VERSION 5.8 ;
BUSBITCHARS "[]" ;
DIVIDERCHAR "/" ;
UNITS
    DATABASE MICRONS 1000 ;
END UNITS

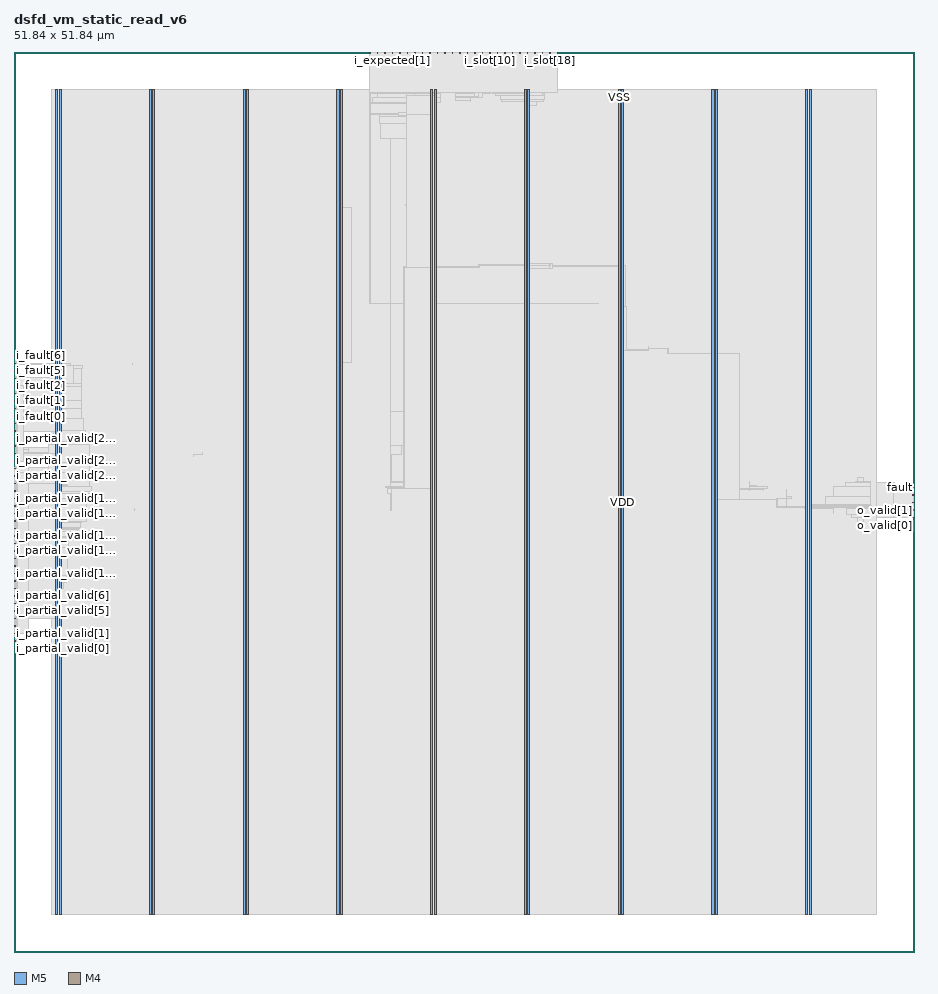
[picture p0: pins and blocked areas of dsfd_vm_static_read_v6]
MACRO dsfd_vm_static_read_v6
  FOREIGN dsfd_vm_static_read_v6 0 0 ;
  CLASS BLOCK ;
  SIZE 51.84 BY 51.84 ;
  PIN ck
    DIRECTION INPUT ;
    USE SIGNAL ;
    PORT
      LAYER M5 ;
        RECT  20.496 51.756 20.52 51.84 ;
    END
  END ck
  PIN fault
    DIRECTION OUTPUT ;
    USE SIGNAL ;
    PORT
      LAYER M4 ;
        RECT  51.756 26.736 51.84 26.76 ;
    END
  END fault
  PIN i_expected[0]
    DIRECTION INPUT ;
    USE SIGNAL ;
    PORT
      LAYER M5 ;
        RECT  21.36 51.756 21.384 51.84 ;
    END
  END i_expected[0]
  PIN i_expected[1]
    DIRECTION INPUT ;
    USE SIGNAL ;
    PORT
      LAYER M5 ;
        RECT  21.792 51.756 21.816 51.84 ;
    END
  END i_expected[1]
  PIN i_expected[2]
    DIRECTION INPUT ;
    USE SIGNAL ;
    PORT
      LAYER M5 ;
        RECT  22.224 51.756 22.248 51.84 ;
    END
  END i_expected[2]
  PIN i_expected[3]
    DIRECTION INPUT ;
    USE SIGNAL ;
    PORT
      LAYER M5 ;
        RECT  22.656 51.756 22.68 51.84 ;
    END
  END i_expected[3]
  PIN i_fault[0]
    DIRECTION INPUT ;
    USE SIGNAL ;
    PORT
      LAYER M4 ;
        RECT  0 31.296 0.084 31.32 ;
    END
  END i_fault[0]
  PIN i_fault[1]
    DIRECTION INPUT ;
    USE SIGNAL ;
    PORT
      LAYER M4 ;
        RECT  0 31.728 0.084 31.752 ;
    END
  END i_fault[1]
  PIN i_fault[2]
    DIRECTION INPUT ;
    USE SIGNAL ;
    PORT
      LAYER M4 ;
        RECT  0 32.16 0.084 32.184 ;
    END
  END i_fault[2]
  PIN i_fault[3]
    DIRECTION INPUT ;
    USE SIGNAL ;
    PORT
      LAYER M4 ;
        RECT  0 32.592 0.084 32.616 ;
    END
  END i_fault[3]
  PIN i_fault[4]
    DIRECTION INPUT ;
    USE SIGNAL ;
    PORT
      LAYER M4 ;
        RECT  0 33.024 0.084 33.048 ;
    END
  END i_fault[4]
  PIN i_fault[5]
    DIRECTION INPUT ;
    USE SIGNAL ;
    PORT
      LAYER M4 ;
        RECT  0 33.456 0.084 33.48 ;
    END
  END i_fault[5]
  PIN i_fault[6]
    DIRECTION INPUT ;
    USE SIGNAL ;
    PORT
      LAYER M4 ;
        RECT  0 33.888 0.084 33.912 ;
    END
  END i_fault[6]
  PIN i_fault[7]
    DIRECTION INPUT ;
    USE SIGNAL ;
    PORT
      LAYER M4 ;
        RECT  0 34.32 0.084 34.344 ;
    END
  END i_fault[7]
  PIN i_partial_valid[0]
    DIRECTION INPUT ;
    USE SIGNAL ;
    PORT
      LAYER M4 ;
        RECT  0 17.472 0.084 17.496 ;
    END
  END i_partial_valid[0]
  PIN i_partial_valid[10]
    DIRECTION INPUT ;
    USE SIGNAL ;
    PORT
      LAYER M4 ;
        RECT  0 21.792 0.084 21.816 ;
    END
  END i_partial_valid[10]
  PIN i_partial_valid[11]
    DIRECTION INPUT ;
    USE SIGNAL ;
    PORT
      LAYER M4 ;
        RECT  0 22.224 0.084 22.248 ;
    END
  END i_partial_valid[11]
  PIN i_partial_valid[12]
    DIRECTION INPUT ;
    USE SIGNAL ;
    PORT
      LAYER M4 ;
        RECT  0 22.656 0.084 22.68 ;
    END
  END i_partial_valid[12]
  PIN i_partial_valid[13]
    DIRECTION INPUT ;
    USE SIGNAL ;
    PORT
      LAYER M4 ;
        RECT  0 23.088 0.084 23.112 ;
    END
  END i_partial_valid[13]
  PIN i_partial_valid[14]
    DIRECTION INPUT ;
    USE SIGNAL ;
    PORT
      LAYER M4 ;
        RECT  0 23.52 0.084 23.544 ;
    END
  END i_partial_valid[14]
  PIN i_partial_valid[15]
    DIRECTION INPUT ;
    USE SIGNAL ;
    PORT
      LAYER M4 ;
        RECT  0 23.952 0.084 23.976 ;
    END
  END i_partial_valid[15]
  PIN i_partial_valid[16]
    DIRECTION INPUT ;
    USE SIGNAL ;
    PORT
      LAYER M4 ;
        RECT  0 24.384 0.084 24.408 ;
    END
  END i_partial_valid[16]
  PIN i_partial_valid[17]
    DIRECTION INPUT ;
    USE SIGNAL ;
    PORT
      LAYER M4 ;
        RECT  0 24.816 0.084 24.84 ;
    END
  END i_partial_valid[17]
  PIN i_partial_valid[18]
    DIRECTION INPUT ;
    USE SIGNAL ;
    PORT
      LAYER M4 ;
        RECT  0 25.248 0.084 25.272 ;
    END
  END i_partial_valid[18]
  PIN i_partial_valid[19]
    DIRECTION INPUT ;
    USE SIGNAL ;
    PORT
      LAYER M4 ;
        RECT  0 25.68 0.084 25.704 ;
    END
  END i_partial_valid[19]
  PIN i_partial_valid[1]
    DIRECTION INPUT ;
    USE SIGNAL ;
    PORT
      LAYER M4 ;
        RECT  0 17.904 0.084 17.928 ;
    END
  END i_partial_valid[1]
  PIN i_partial_valid[20]
    DIRECTION INPUT ;
    USE SIGNAL ;
    PORT
      LAYER M4 ;
        RECT  0 26.112 0.084 26.136 ;
    END
  END i_partial_valid[20]
  PIN i_partial_valid[21]
    DIRECTION INPUT ;
    USE SIGNAL ;
    PORT
      LAYER M4 ;
        RECT  0 26.544 0.084 26.568 ;
    END
  END i_partial_valid[21]
  PIN i_partial_valid[22]
    DIRECTION INPUT ;
    USE SIGNAL ;
    PORT
      LAYER M4 ;
        RECT  0 26.976 0.084 27 ;
    END
  END i_partial_valid[22]
  PIN i_partial_valid[23]
    DIRECTION INPUT ;
    USE SIGNAL ;
    PORT
      LAYER M4 ;
        RECT  0 27.408 0.084 27.432 ;
    END
  END i_partial_valid[23]
  PIN i_partial_valid[24]
    DIRECTION INPUT ;
    USE SIGNAL ;
    PORT
      LAYER M4 ;
        RECT  0 27.84 0.084 27.864 ;
    END
  END i_partial_valid[24]
  PIN i_partial_valid[25]
    DIRECTION INPUT ;
    USE SIGNAL ;
    PORT
      LAYER M4 ;
        RECT  0 28.272 0.084 28.296 ;
    END
  END i_partial_valid[25]
  PIN i_partial_valid[26]
    DIRECTION INPUT ;
    USE SIGNAL ;
    PORT
      LAYER M4 ;
        RECT  0 28.704 0.084 28.728 ;
    END
  END i_partial_valid[26]
  PIN i_partial_valid[27]
    DIRECTION INPUT ;
    USE SIGNAL ;
    PORT
      LAYER M4 ;
        RECT  0 29.136 0.084 29.16 ;
    END
  END i_partial_valid[27]
  PIN i_partial_valid[28]
    DIRECTION INPUT ;
    USE SIGNAL ;
    PORT
      LAYER M4 ;
        RECT  0 29.568 0.084 29.592 ;
    END
  END i_partial_valid[28]
  PIN i_partial_valid[29]
    DIRECTION INPUT ;
    USE SIGNAL ;
    PORT
      LAYER M4 ;
        RECT  0 30 0.084 30.024 ;
    END
  END i_partial_valid[29]
  PIN i_partial_valid[2]
    DIRECTION INPUT ;
    USE SIGNAL ;
    PORT
      LAYER M4 ;
        RECT  0 18.336 0.084 18.36 ;
    END
  END i_partial_valid[2]
  PIN i_partial_valid[30]
    DIRECTION INPUT ;
    USE SIGNAL ;
    PORT
      LAYER M4 ;
        RECT  0 30.432 0.084 30.456 ;
    END
  END i_partial_valid[30]
  PIN i_partial_valid[31]
    DIRECTION INPUT ;
    USE SIGNAL ;
    PORT
      LAYER M4 ;
        RECT  0 30.864 0.084 30.888 ;
    END
  END i_partial_valid[31]
  PIN i_partial_valid[3]
    DIRECTION INPUT ;
    USE SIGNAL ;
    PORT
      LAYER M4 ;
        RECT  0 18.768 0.084 18.792 ;
    END
  END i_partial_valid[3]
  PIN i_partial_valid[4]
    DIRECTION INPUT ;
    USE SIGNAL ;
    PORT
      LAYER M4 ;
        RECT  0 19.2 0.084 19.224 ;
    END
  END i_partial_valid[4]
  PIN i_partial_valid[5]
    DIRECTION INPUT ;
    USE SIGNAL ;
    PORT
      LAYER M4 ;
        RECT  0 19.632 0.084 19.656 ;
    END
  END i_partial_valid[5]
  PIN i_partial_valid[6]
    DIRECTION INPUT ;
    USE SIGNAL ;
    PORT
      LAYER M4 ;
        RECT  0 20.064 0.084 20.088 ;
    END
  END i_partial_valid[6]
  PIN i_partial_valid[7]
    DIRECTION INPUT ;
    USE SIGNAL ;
    PORT
      LAYER M4 ;
        RECT  0 20.496 0.084 20.52 ;
    END
  END i_partial_valid[7]
  PIN i_partial_valid[8]
    DIRECTION INPUT ;
    USE SIGNAL ;
    PORT
      LAYER M4 ;
        RECT  0 20.928 0.084 20.952 ;
    END
  END i_partial_valid[8]
  PIN i_partial_valid[9]
    DIRECTION INPUT ;
    USE SIGNAL ;
    PORT
      LAYER M4 ;
        RECT  0 21.36 0.084 21.384 ;
    END
  END i_partial_valid[9]
  PIN i_slot[0]
    DIRECTION INPUT ;
    USE SIGNAL ;
    PORT
      LAYER M5 ;
        RECT  23.088 51.756 23.112 51.84 ;
    END
  END i_slot[0]
  PIN i_slot[10]
    DIRECTION INPUT ;
    USE SIGNAL ;
    PORT
      LAYER M5 ;
        RECT  27.408 51.756 27.432 51.84 ;
    END
  END i_slot[10]
  PIN i_slot[11]
    DIRECTION INPUT ;
    USE SIGNAL ;
    PORT
      LAYER M5 ;
        RECT  27.84 51.756 27.864 51.84 ;
    END
  END i_slot[11]
  PIN i_slot[12]
    DIRECTION INPUT ;
    USE SIGNAL ;
    PORT
      LAYER M5 ;
        RECT  28.272 51.756 28.296 51.84 ;
    END
  END i_slot[12]
  PIN i_slot[13]
    DIRECTION INPUT ;
    USE SIGNAL ;
    PORT
      LAYER M5 ;
        RECT  28.704 51.756 28.728 51.84 ;
    END
  END i_slot[13]
  PIN i_slot[14]
    DIRECTION INPUT ;
    USE SIGNAL ;
    PORT
      LAYER M5 ;
        RECT  29.136 51.756 29.16 51.84 ;
    END
  END i_slot[14]
  PIN i_slot[15]
    DIRECTION INPUT ;
    USE SIGNAL ;
    PORT
      LAYER M5 ;
        RECT  29.568 51.756 29.592 51.84 ;
    END
  END i_slot[15]
  PIN i_slot[16]
    DIRECTION INPUT ;
    USE SIGNAL ;
    PORT
      LAYER M5 ;
        RECT  30 51.756 30.024 51.84 ;
    END
  END i_slot[16]
  PIN i_slot[17]
    DIRECTION INPUT ;
    USE SIGNAL ;
    PORT
      LAYER M5 ;
        RECT  30.432 51.756 30.456 51.84 ;
    END
  END i_slot[17]
  PIN i_slot[18]
    DIRECTION INPUT ;
    USE SIGNAL ;
    PORT
      LAYER M5 ;
        RECT  30.864 51.756 30.888 51.84 ;
    END
  END i_slot[18]
  PIN i_slot[19]
    DIRECTION INPUT ;
    USE SIGNAL ;
    PORT
      LAYER M5 ;
        RECT  31.296 51.756 31.32 51.84 ;
    END
  END i_slot[19]
  PIN i_slot[1]
    DIRECTION INPUT ;
    USE SIGNAL ;
    PORT
      LAYER M5 ;
        RECT  23.52 51.756 23.544 51.84 ;
    END
  END i_slot[1]
  PIN i_slot[2]
    DIRECTION INPUT ;
    USE SIGNAL ;
    PORT
      LAYER M5 ;
        RECT  23.952 51.756 23.976 51.84 ;
    END
  END i_slot[2]
  PIN i_slot[3]
    DIRECTION INPUT ;
    USE SIGNAL ;
    PORT
      LAYER M5 ;
        RECT  24.384 51.756 24.408 51.84 ;
    END
  END i_slot[3]
  PIN i_slot[4]
    DIRECTION INPUT ;
    USE SIGNAL ;
    PORT
      LAYER M5 ;
        RECT  24.816 51.756 24.84 51.84 ;
    END
  END i_slot[4]
  PIN i_slot[5]
    DIRECTION INPUT ;
    USE SIGNAL ;
    PORT
      LAYER M5 ;
        RECT  25.248 51.756 25.272 51.84 ;
    END
  END i_slot[5]
  PIN i_slot[6]
    DIRECTION INPUT ;
    USE SIGNAL ;
    PORT
      LAYER M5 ;
        RECT  25.68 51.756 25.704 51.84 ;
    END
  END i_slot[6]
  PIN i_slot[7]
    DIRECTION INPUT ;
    USE SIGNAL ;
    PORT
      LAYER M5 ;
        RECT  26.112 51.756 26.136 51.84 ;
    END
  END i_slot[7]
  PIN i_slot[8]
    DIRECTION INPUT ;
    USE SIGNAL ;
    PORT
      LAYER M5 ;
        RECT  26.544 51.756 26.568 51.84 ;
    END
  END i_slot[8]
  PIN i_slot[9]
    DIRECTION INPUT ;
    USE SIGNAL ;
    PORT
      LAYER M5 ;
        RECT  26.976 51.756 27 51.84 ;
    END
  END i_slot[9]
  PIN o_valid[0]
    DIRECTION OUTPUT ;
    USE SIGNAL ;
    PORT
      LAYER M4 ;
        RECT  51.756 25.008 51.84 25.032 ;
    END
  END o_valid[0]
  PIN o_valid[1]
    DIRECTION OUTPUT ;
    USE SIGNAL ;
    PORT
      LAYER M4 ;
        RECT  51.756 25.44 51.84 25.464 ;
    END
  END o_valid[1]
  PIN o_valid[2]
    DIRECTION OUTPUT ;
    USE SIGNAL ;
    PORT
      LAYER M4 ;
        RECT  51.756 25.872 51.84 25.896 ;
    END
  END o_valid[2]
  PIN o_valid[3]
    DIRECTION OUTPUT ;
    USE SIGNAL ;
    PORT
      LAYER M4 ;
        RECT  51.756 26.304 51.84 26.328 ;
    END
  END o_valid[3]
  PIN rst_n
    DIRECTION INPUT ;
    USE SIGNAL ;
    PORT
      LAYER M5 ;
        RECT  20.928 51.756 20.952 51.84 ;
    END
  END rst_n
  PIN VDD
    DIRECTION INOUT ;
    USE POWER ;
    PORT
      LAYER M5 ;
        RECT  45.792 2.151 45.912 49.689 ;
        RECT  40.392 2.151 40.512 49.689 ;
        RECT  34.992 2.151 35.112 49.689 ;
        RECT  29.592 2.151 29.712 49.689 ;
        RECT  24.192 2.151 24.312 49.689 ;
        RECT  18.792 2.151 18.912 49.689 ;
        RECT  13.392 2.151 13.512 49.689 ;
        RECT  7.992 2.151 8.112 49.689 ;
        RECT  2.592 2.151 2.712 49.689 ;
    END
  END VDD
  PIN VSS
    DIRECTION INOUT ;
    USE GROUND ;
    PORT
      LAYER M5 ;
        RECT  45.6 2.137 45.72 49.703 ;
        RECT  40.2 2.137 40.32 49.703 ;
        RECT  34.8 2.137 34.92 49.703 ;
        RECT  29.4 2.137 29.52 49.703 ;
        RECT  24 2.137 24.12 49.703 ;
        RECT  18.6 2.137 18.72 49.703 ;
        RECT  13.2 2.137 13.32 49.703 ;
        RECT  7.8 2.137 7.92 49.703 ;
        RECT  2.4 2.137 2.52 49.703 ;
    END
  END VSS
  # OT_OBS_CLOSED layer=M5 d_um=1.536 added=6
  OBS
    LAYER RVTN ;
     RECT  2.16 2.16 49.68 2.295 ;
     RECT  2.16 2.565 49.68 2.835 ;
     RECT  2.16 3.105 49.68 3.375 ;
     RECT  2.16 3.645 49.68 3.915 ;
     RECT  2.16 4.185 49.68 4.455 ;
     RECT  2.16 4.725 49.68 4.995 ;
     RECT  2.16 5.265 49.68 5.535 ;
     RECT  2.16 5.805 49.68 6.075 ;
     RECT  2.16 6.345 49.68 6.615 ;
     RECT  2.16 6.885 49.68 7.155 ;
     RECT  2.16 7.425 49.68 7.695 ;
     RECT  2.16 7.965 49.68 8.235 ;
     RECT  2.16 8.505 49.68 8.775 ;
     RECT  2.16 9.045 49.68 9.315 ;
     RECT  2.16 9.585 49.68 9.855 ;
     RECT  2.16 10.125 49.68 10.395 ;
     RECT  2.16 10.665 49.68 10.935 ;
     RECT  2.16 11.205 49.68 11.475 ;
     RECT  2.16 11.745 49.68 12.015 ;
     RECT  2.16 12.285 49.68 12.555 ;
     RECT  2.16 12.825 49.68 13.095 ;
     RECT  2.16 13.365 49.68 13.635 ;
     RECT  2.16 13.905 49.68 14.175 ;
     RECT  2.16 14.445 49.68 14.715 ;
     RECT  2.16 14.985 49.68 15.255 ;
     RECT  2.16 15.525 49.68 15.795 ;
     RECT  2.16 16.065 49.68 16.335 ;
     RECT  2.16 16.605 49.68 16.875 ;
     RECT  2.16 17.145 49.68 17.415 ;
     RECT  2.16 17.685 49.68 17.955 ;
     RECT  2.16 18.225 49.68 18.495 ;
     RECT  2.16 18.765 49.68 19.035 ;
     RECT  2.16 19.305 49.68 19.575 ;
     RECT  2.16 19.845 49.68 20.115 ;
     RECT  2.16 20.385 49.68 20.655 ;
     RECT  2.16 20.925 49.68 21.195 ;
     RECT  2.16 21.465 49.68 21.735 ;
     RECT  2.16 22.005 49.68 22.275 ;
     RECT  2.16 22.545 49.68 22.815 ;
     RECT  2.16 23.085 49.68 23.355 ;
     RECT  2.16 23.625 49.68 23.895 ;
     RECT  2.16 24.165 49.68 24.435 ;
     RECT  2.16 24.705 49.68 24.975 ;
     RECT  2.16 25.245 49.68 25.515 ;
     RECT  2.16 25.785 49.68 26.055 ;
     RECT  2.16 26.325 49.68 26.595 ;
     RECT  2.16 26.865 49.68 27.135 ;
     RECT  2.16 27.405 49.68 27.675 ;
     RECT  2.16 27.945 49.68 28.215 ;
     RECT  2.16 28.485 49.68 28.755 ;
     RECT  2.16 29.025 49.68 29.295 ;
     RECT  2.16 29.565 49.68 29.835 ;
     RECT  2.16 30.105 49.68 30.375 ;
     RECT  2.16 30.645 49.68 30.915 ;
     RECT  2.16 31.185 49.68 31.455 ;
     RECT  2.16 31.725 49.68 31.995 ;
     RECT  2.16 32.265 49.68 32.535 ;
     RECT  2.16 32.805 49.68 33.075 ;
     RECT  2.16 33.345 49.68 33.615 ;
     RECT  2.16 33.885 49.68 34.155 ;
     RECT  2.16 34.425 49.68 34.695 ;
     RECT  2.16 34.965 49.68 35.235 ;
     RECT  2.16 35.505 49.68 35.775 ;
     RECT  2.16 36.045 49.68 36.315 ;
     RECT  2.16 36.585 49.68 36.855 ;
     RECT  2.16 37.125 49.68 37.395 ;
     RECT  2.16 37.665 49.68 37.935 ;
     RECT  2.16 38.205 49.68 38.475 ;
     RECT  2.16 38.745 49.68 39.015 ;
     RECT  2.16 39.285 49.68 39.555 ;
     RECT  2.16 39.825 49.68 40.095 ;
     RECT  2.16 40.365 49.68 40.635 ;
     RECT  2.16 40.905 49.68 41.175 ;
     RECT  2.16 41.445 49.68 41.715 ;
     RECT  2.16 41.985 49.68 42.255 ;
     RECT  2.16 42.525 49.68 42.795 ;
     RECT  2.16 43.065 49.68 43.335 ;
     RECT  2.16 43.605 49.68 43.875 ;
     RECT  2.16 44.145 49.68 44.415 ;
     RECT  2.16 44.685 49.68 44.955 ;
     RECT  2.16 45.225 49.68 45.495 ;
     RECT  2.16 45.765 49.68 46.035 ;
     RECT  2.16 46.305 49.68 46.575 ;
     RECT  2.16 46.845 49.68 47.115 ;
     RECT  2.16 47.385 49.68 47.655 ;
     RECT  2.16 47.925 49.68 48.195 ;
     RECT  2.16 48.465 49.68 48.735 ;
     RECT  2.16 49.005 49.68 49.275 ;
     RECT  2.16 49.545 49.68 49.68 ;
    LAYER RVTP ;
     RECT  2.16 2.295 49.68 2.565 ;
     RECT  2.16 2.835 49.68 3.105 ;
     RECT  2.16 3.375 49.68 3.645 ;
     RECT  2.16 3.915 49.68 4.185 ;
     RECT  2.16 4.455 49.68 4.725 ;
     RECT  2.16 4.995 49.68 5.265 ;
     RECT  2.16 5.535 49.68 5.805 ;
     RECT  2.16 6.075 49.68 6.345 ;
     RECT  2.16 6.615 49.68 6.885 ;
     RECT  2.16 7.155 49.68 7.425 ;
     RECT  2.16 7.695 49.68 7.965 ;
     RECT  2.16 8.235 49.68 8.505 ;
     RECT  2.16 8.775 49.68 9.045 ;
     RECT  2.16 9.315 49.68 9.585 ;
     RECT  2.16 9.855 49.68 10.125 ;
     RECT  2.16 10.395 49.68 10.665 ;
     RECT  2.16 10.935 49.68 11.205 ;
     RECT  2.16 11.475 49.68 11.745 ;
     RECT  2.16 12.015 49.68 12.285 ;
     RECT  2.16 12.555 49.68 12.825 ;
     RECT  2.16 13.095 49.68 13.365 ;
     RECT  2.16 13.635 49.68 13.905 ;
     RECT  2.16 14.175 49.68 14.445 ;
     RECT  2.16 14.715 49.68 14.985 ;
     RECT  2.16 15.255 49.68 15.525 ;
     RECT  2.16 15.795 49.68 16.065 ;
     RECT  2.16 16.335 49.68 16.605 ;
     RECT  2.16 16.875 49.68 17.145 ;
     RECT  2.16 17.415 49.68 17.685 ;
     RECT  2.16 17.955 49.68 18.225 ;
     RECT  2.16 18.495 49.68 18.765 ;
     RECT  2.16 19.035 49.68 19.305 ;
     RECT  2.16 19.575 49.68 19.845 ;
     RECT  2.16 20.115 49.68 20.385 ;
     RECT  2.16 20.655 49.68 20.925 ;
     RECT  2.16 21.195 49.68 21.465 ;
     RECT  2.16 21.735 49.68 22.005 ;
     RECT  2.16 22.275 49.68 22.545 ;
     RECT  2.16 22.815 49.68 23.085 ;
     RECT  2.16 23.355 49.68 23.625 ;
     RECT  2.16 23.895 49.68 24.165 ;
     RECT  2.16 24.435 49.68 24.705 ;
     RECT  2.16 24.975 49.68 25.245 ;
     RECT  2.16 25.515 49.68 25.785 ;
     RECT  2.16 26.055 49.68 26.325 ;
     RECT  2.16 26.595 49.68 26.865 ;
     RECT  2.16 27.135 49.68 27.405 ;
     RECT  2.16 27.675 49.68 27.945 ;
     RECT  2.16 28.215 49.68 28.485 ;
     RECT  2.16 28.755 49.68 29.025 ;
     RECT  2.16 29.295 49.68 29.565 ;
     RECT  2.16 29.835 49.68 30.105 ;
     RECT  2.16 30.375 49.68 30.645 ;
     RECT  2.16 30.915 49.68 31.185 ;
     RECT  2.16 31.455 49.68 31.725 ;
     RECT  2.16 31.995 49.68 32.265 ;
     RECT  2.16 32.535 49.68 32.805 ;
     RECT  2.16 33.075 49.68 33.345 ;
     RECT  2.16 33.615 49.68 33.885 ;
     RECT  2.16 34.155 49.68 34.425 ;
     RECT  2.16 34.695 49.68 34.965 ;
     RECT  2.16 35.235 49.68 35.505 ;
     RECT  2.16 35.775 49.68 36.045 ;
     RECT  2.16 36.315 49.68 36.585 ;
     RECT  2.16 36.855 49.68 37.125 ;
     RECT  2.16 37.395 49.68 37.665 ;
     RECT  2.16 37.935 49.68 38.205 ;
     RECT  2.16 38.475 49.68 38.745 ;
     RECT  2.16 39.015 49.68 39.285 ;
     RECT  2.16 39.555 49.68 39.825 ;
     RECT  2.16 40.095 49.68 40.365 ;
     RECT  2.16 40.635 49.68 40.905 ;
     RECT  2.16 41.175 49.68 41.445 ;
     RECT  2.16 41.715 49.68 41.985 ;
     RECT  2.16 42.255 49.68 42.525 ;
     RECT  2.16 42.795 49.68 43.065 ;
     RECT  2.16 43.335 49.68 43.605 ;
     RECT  2.16 43.875 49.68 44.145 ;
     RECT  2.16 44.415 49.68 44.685 ;
     RECT  2.16 44.955 49.68 45.225 ;
     RECT  2.16 45.495 49.68 45.765 ;
     RECT  2.16 46.035 49.68 46.305 ;
     RECT  2.16 46.575 49.68 46.845 ;
     RECT  2.16 47.115 49.68 47.385 ;
     RECT  2.16 47.655 49.68 47.925 ;
     RECT  2.16 48.195 49.68 48.465 ;
     RECT  2.16 48.735 49.68 49.005 ;
     RECT  2.16 49.275 49.68 49.545 ;
    LAYER M1 ;
     RECT  2.16 2.151 49.68 49.689 ;
    LAYER M2 ;
     RECT  0.031 27.882 0.067 27.9 ;
     RECT  0.067 27.342 0.103 27.9 ;
     RECT  0.103 26.64 0.139 27.9 ;
     RECT  0.103 31.896 0.139 32.328 ;
     RECT  0.067 20.511 0.167 20.529 ;
     RECT  0.103 22.824 0.175 22.842 ;
     RECT  0.139 26.262 0.175 27.9 ;
     RECT  0.175 22.212 0.203 22.842 ;
     RECT  0.103 28.962 0.535 28.98 ;
     RECT  0.535 28.8 0.823 28.98 ;
     RECT  0.203 22.212 1.723 22.23 ;
     RECT  0.823 28.8 1.975 29.052 ;
     RECT  1.723 21.672 2.16 22.23 ;
     RECT  0.175 26.262 2.16 27.936 ;
     RECT  1.975 28.8 2.16 29.25 ;
     RECT  0.139 31.896 2.16 33.066 ;
     RECT  0.103 33.858 2.16 33.876 ;
     RECT  2.16 2.151 49.68 49.689 ;
     RECT  49.68 25.02 50.711 27.054 ;
     RECT  50.711 25.596 50.747 25.614 ;
    LAYER M3 ;
     RECT  2.415 2.143 2.505 2.413 ;
     RECT  7.815 2.143 7.905 2.413 ;
     RECT  13.215 2.143 13.305 2.413 ;
     RECT  18.615 2.143 18.705 2.413 ;
     RECT  24.015 2.143 24.105 2.413 ;
     RECT  29.415 2.143 29.505 2.413 ;
     RECT  34.815 2.143 34.905 2.413 ;
     RECT  40.215 2.143 40.305 2.413 ;
     RECT  45.615 2.143 45.705 2.413 ;
     RECT  0.18 17.467 0.198 17.899 ;
     RECT  0.108 17.899 0.198 18.187 ;
     RECT  0.036 18.187 0.198 18.331 ;
     RECT  2.415 2.413 2.697 19.195 ;
     RECT  0.036 18.331 0.846 19.627 ;
     RECT  1.728 19.195 2.697 19.627 ;
     RECT  0.036 19.627 2.697 20.923 ;
     RECT  0.036 20.923 2.862 21.271 ;
     RECT  0.036 21.271 3.042 21.703 ;
     RECT  0.036 21.703 3.078 23.323 ;
     RECT  0.036 23.323 3.114 23.629 ;
     RECT  0.036 23.629 3.15 23.701 ;
     RECT  0.036 23.701 3.222 23.899 ;
     RECT  0.036 23.899 3.546 24.241 ;
     RECT  0.036 24.241 3.654 24.331 ;
     RECT  0.036 24.331 3.69 24.403 ;
     RECT  0.036 24.403 3.798 24.475 ;
     RECT  0.036 24.475 3.834 24.745 ;
     RECT  0.036 24.745 3.906 24.781 ;
     RECT  48.6 24.745 48.618 24.781 ;
     RECT  48.6 24.781 48.942 25.051 ;
     RECT  48.24 25.051 48.942 25.177 ;
     RECT  47.988 25.177 48.942 25.213 ;
     RECT  50.688 25.003 50.706 25.475 ;
     RECT  45.615 2.413 45.897 25.519 ;
     RECT  47.196 25.249 47.214 25.519 ;
     RECT  45.615 25.519 47.214 25.531 ;
     RECT  6.912 25.447 6.93 25.547 ;
     RECT  47.952 25.213 48.942 25.555 ;
     RECT  45.54 25.531 47.214 25.591 ;
     RECT  47.952 25.555 49.374 25.591 ;
     RECT  45.54 25.591 49.374 25.661 ;
     RECT  43.92 25.627 43.938 25.681 ;
     RECT  45.612 25.661 49.374 25.709 ;
     RECT  45.612 25.709 49.338 25.781 ;
     RECT  50.724 25.591 50.742 25.901 ;
     RECT  43.92 25.681 44.514 26.093 ;
     RECT  44.496 26.093 44.514 26.095 ;
     RECT  0.036 24.781 4.158 26.131 ;
     RECT  44.496 26.095 44.802 26.249 ;
     RECT  46.764 25.781 49.338 26.249 ;
     RECT  45.612 25.781 45.897 26.285 ;
     RECT  0.036 26.131 4.23 26.401 ;
     RECT  21.708 25.447 21.726 26.401 ;
     RECT  0.036 26.401 4.482 26.519 ;
     RECT  44.496 26.249 44.514 26.627 ;
     RECT  42.336 26.599 42.354 26.629 ;
     RECT  41.76 26.629 42.354 26.635 ;
     RECT  43.164 26.599 43.182 26.635 ;
     RECT  41.76 26.635 43.182 26.669 ;
     RECT  21.528 26.401 21.726 26.671 ;
     RECT  42.336 26.669 43.182 26.671 ;
     RECT  21.528 26.671 22.806 26.731 ;
     RECT  0.036 26.519 4.446 26.789 ;
     RECT  21.384 26.731 22.806 26.789 ;
     RECT  42.336 26.671 43.398 26.789 ;
     RECT  47.196 26.249 49.338 26.789 ;
     RECT  42.336 26.789 43.254 26.825 ;
     RECT  42.336 26.825 42.75 26.861 ;
     RECT  47.88 26.789 49.338 27.059 ;
     RECT  50.688 26.293 50.706 27.059 ;
     RECT  21.708 26.789 22.806 27.067 ;
     RECT  21.708 27.067 23.166 27.095 ;
     RECT  42.336 26.861 42.354 27.095 ;
     RECT  48.456 27.059 49.338 27.095 ;
     RECT  48.564 27.095 48.942 27.329 ;
     RECT  0.036 26.789 4.338 27.635 ;
     RECT  22.644 27.095 23.166 27.779 ;
     RECT  0.036 27.635 0.846 27.905 ;
     RECT  0.18 27.905 0.846 27.941 ;
     RECT  10.332 28.561 10.35 28.651 ;
     RECT  21.708 27.095 21.726 28.651 ;
     RECT  10.332 28.651 10.854 28.679 ;
     RECT  10.836 28.679 10.854 28.751 ;
     RECT  0.828 27.941 0.846 28.795 ;
     RECT  0.54 28.795 0.846 28.957 ;
     RECT  0.108 28.957 0.846 29.057 ;
     RECT  0.108 29.057 0.558 29.165 ;
     RECT  21.708 28.651 22.338 29.191 ;
     RECT  23.148 27.779 23.166 29.191 ;
     RECT  1.98 27.635 4.338 29.219 ;
     RECT  1.98 29.219 4.194 29.255 ;
     RECT  2.304 29.255 4.194 29.399 ;
     RECT  0.108 29.165 0.126 29.597 ;
     RECT  2.304 29.399 4.122 30.029 ;
     RECT  2.415 30.029 3.978 30.749 ;
     RECT  21.708 29.191 23.166 31.117 ;
     RECT  24.015 2.413 24.297 31.117 ;
     RECT  2.415 30.749 3.87 31.291 ;
     RECT  2.304 31.291 3.87 31.757 ;
     RECT  2.415 31.757 3.87 32.587 ;
     RECT  2.304 32.587 3.87 32.729 ;
     RECT  0.108 31.891 0.126 33.043 ;
     RECT  0.108 33.043 0.162 33.053 ;
     RECT  0.144 33.053 0.162 33.485 ;
     RECT  3.42 32.729 3.87 33.619 ;
     RECT  2.415 32.729 2.697 33.781 ;
     RECT  3.42 33.619 3.942 33.781 ;
     RECT  2.415 33.781 3.942 33.809 ;
     RECT  2.415 33.809 3.258 33.881 ;
     RECT  2.415 33.881 2.697 33.883 ;
     RECT  6.804 33.817 6.822 33.917 ;
     RECT  2.304 33.883 2.697 33.953 ;
     RECT  18.615 2.413 18.897 33.961 ;
     RECT  0.108 33.853 0.126 34.349 ;
     RECT  36.504 34.651 36.522 34.691 ;
     RECT  37.656 34.459 37.674 34.781 ;
     RECT  36.54 34.747 36.558 34.889 ;
     RECT  33.624 37.327 33.642 37.373 ;
     RECT  30.636 39.355 30.978 39.479 ;
     RECT  26.784 39.451 26.802 39.581 ;
     RECT  30.96 39.479 30.978 39.677 ;
     RECT  18.615 33.961 19.422 42.899 ;
     RECT  21.708 31.117 24.297 46.885 ;
     RECT  21.132 46.885 24.297 47.731 ;
     RECT  21.06 47.731 24.297 48.119 ;
     RECT  21.06 48.119 23.058 48.229 ;
     RECT  20.484 48.229 23.058 48.269 ;
     RECT  23.94 48.119 24.297 48.631 ;
     RECT  29.415 2.413 29.697 48.775 ;
     RECT  20.52 48.269 23.058 48.901 ;
     RECT  23.94 48.631 24.354 48.901 ;
     RECT  20.52 48.901 24.354 48.929 ;
     RECT  20.664 48.929 24.354 48.937 ;
     RECT  29.415 48.775 30.114 48.973 ;
     RECT  28.08 48.973 30.114 49.009 ;
     RECT  26.28 48.973 26.298 49.045 ;
     RECT  28.08 49.009 30.474 49.081 ;
     RECT  20.664 48.937 24.57 49.199 ;
     RECT  25.452 49.045 26.298 49.237 ;
     RECT  25.452 49.237 26.802 49.277 ;
     RECT  28.008 49.081 30.582 49.315 ;
     RECT  2.415 33.953 2.697 49.427 ;
     RECT  7.815 2.413 8.097 49.427 ;
     RECT  13.215 2.413 13.497 49.427 ;
     RECT  18.615 42.899 18.897 49.427 ;
     RECT  34.815 2.413 35.097 49.427 ;
     RECT  40.215 2.413 40.497 49.427 ;
     RECT  45.615 26.285 45.897 49.427 ;
     RECT  20.916 49.199 24.57 49.469 ;
     RECT  25.452 49.277 26.55 49.469 ;
     RECT  27.756 49.315 30.582 49.477 ;
     RECT  20.988 49.469 22.662 49.517 ;
     RECT  27.576 49.477 30.582 49.517 ;
     RECT  25.452 49.469 26.442 49.531 ;
     RECT  27.9 49.517 30.582 49.531 ;
     RECT  27.9 49.531 30.978 49.565 ;
     RECT  21.096 49.517 21.654 49.577 ;
     RECT  22.644 49.517 22.662 49.577 ;
     RECT  23.508 49.469 24.462 49.577 ;
     RECT  25.236 49.531 26.442 49.577 ;
     RECT  27.9 49.565 27.918 49.577 ;
     RECT  29.415 49.565 30.978 49.577 ;
     RECT  30.456 49.577 30.546 49.649 ;
     RECT  2.415 49.427 2.505 49.697 ;
     RECT  7.815 49.427 7.905 49.697 ;
     RECT  13.215 49.427 13.305 49.697 ;
     RECT  18.615 49.427 18.705 49.697 ;
     RECT  29.415 49.577 29.61 49.697 ;
     RECT  34.815 49.427 34.905 49.697 ;
     RECT  40.215 49.427 40.305 49.697 ;
     RECT  45.615 49.427 45.705 49.697 ;
     RECT  29.592 49.697 29.61 49.805 ;
     RECT  23.904 49.577 24.462 50.765 ;
     RECT  30.528 49.649 30.546 50.765 ;
    LAYER M4 ;
     RECT  0.025 18.192 0.06 18.216 ;
     RECT  0.06 17.472 0.137 34.344 ;
     RECT  0.137 17.472 0.173 33.912 ;
     RECT  0.173 17.472 0.209 27 ;
     RECT  0.173 28.272 0.569 32.616 ;
     RECT  0.209 18.336 0.857 27 ;
     RECT  0.857 19.2 2.408 27 ;
     RECT  0.569 28.272 2.408 28.728 ;
     RECT  0.569 30 2.408 32.616 ;
     RECT  0.173 33.888 2.408 33.912 ;
     RECT  2.408 2.148 2.512 49.692 ;
     RECT  2.512 2.418 2.704 49.422 ;
     RECT  2.704 20.928 2.873 20.952 ;
     RECT  2.704 26.88 3.053 26.904 ;
     RECT  2.704 23.904 3.557 23.928 ;
     RECT  2.704 28.176 3.593 28.2 ;
     RECT  7.808 2.148 7.912 49.692 ;
     RECT  7.912 2.418 8.104 49.422 ;
     RECT  13.208 2.148 13.312 49.692 ;
     RECT  13.312 2.418 13.504 49.422 ;
     RECT  18.608 2.148 18.712 49.692 ;
     RECT  18.712 2.418 18.904 49.422 ;
     RECT  20.473 48.24 21.089 48.264 ;
     RECT  21.373 26.736 22.499 26.76 ;
     RECT  20.917 49.488 22.604 49.512 ;
     RECT  22.556 43.008 22.643 43.032 ;
     RECT  22.165 48.192 22.643 48.36 ;
     RECT  22.604 49.488 22.705 49.56 ;
     RECT  22.705 48.96 22.997 49.56 ;
     RECT  20.485 37.344 24.008 37.368 ;
     RECT  22.453 39.456 24.008 39.48 ;
     RECT  22.997 49.344 24.008 49.56 ;
     RECT  24.008 2.148 24.112 49.692 ;
     RECT  24.112 2.418 24.304 49.56 ;
     RECT  23.893 50.736 24.851 50.76 ;
     RECT  24.304 49.536 26.579 49.56 ;
     RECT  24.304 39.456 26.773 39.48 ;
     RECT  26.773 39.456 26.813 39.576 ;
     RECT  26.773 49.248 27.011 49.512 ;
     RECT  27.011 49.488 27.605 49.512 ;
     RECT  24.304 37.344 29.408 37.368 ;
     RECT  26.813 39.552 29.408 39.576 ;
     RECT  27.829 49.536 29.408 49.56 ;
     RECT  29.408 2.148 29.512 49.692 ;
     RECT  29.512 2.418 29.557 49.692 ;
     RECT  29.557 2.418 29.644 49.8 ;
     RECT  29.644 2.418 29.704 49.422 ;
     RECT  29.704 49.344 30.467 49.368 ;
     RECT  29.704 39.36 30.853 39.576 ;
     RECT  30.517 50.736 30.899 50.76 ;
     RECT  30.853 39.36 30.989 39.672 ;
     RECT  30.949 49.536 31.331 49.56 ;
     RECT  29.704 37.344 33.653 37.368 ;
     RECT  30.989 39.504 34.808 39.528 ;
     RECT  34.808 2.148 34.912 49.692 ;
     RECT  34.912 2.418 35.104 49.422 ;
     RECT  35.104 37.152 35.219 37.368 ;
     RECT  35.104 39.504 35.219 39.528 ;
     RECT  35.219 37.152 35.267 37.176 ;
     RECT  35.104 34.656 36.529 34.68 ;
     RECT  36.529 34.656 36.533 34.776 ;
     RECT  36.533 34.752 37.645 34.776 ;
     RECT  37.645 34.464 37.685 34.776 ;
     RECT  37.685 34.464 40.208 34.488 ;
     RECT  40.208 2.148 40.312 49.692 ;
     RECT  40.312 2.418 40.504 49.422 ;
     RECT  41.708 26.64 41.749 26.664 ;
     RECT  41.749 26.064 41.795 26.664 ;
     RECT  40.504 34.464 41.795 34.488 ;
     RECT  41.795 26.064 43.909 26.088 ;
     RECT  43.909 25.632 43.949 26.088 ;
     RECT  43.949 25.632 45.529 25.656 ;
     RECT  45.529 25.536 45.608 25.656 ;
     RECT  45.608 2.148 45.712 49.692 ;
     RECT  45.712 2.418 45.904 49.422 ;
     RECT  45.904 25.536 47.225 25.56 ;
     RECT  50.677 25.008 51.804 26.76 ;
    LAYER M5 ;
     RECT  2.4 2.137 2.52 2.151 ;
     RECT  7.8 2.137 7.92 2.151 ;
     RECT  13.2 2.137 13.32 2.151 ;
     RECT  18.6 2.137 18.72 2.151 ;
     RECT  24 2.137 24.12 2.151 ;
     RECT  29.4 2.137 29.52 2.151 ;
     RECT  34.8 2.137 34.92 2.151 ;
     RECT  40.2 2.137 40.32 2.151 ;
     RECT  45.6 2.137 45.72 2.151 ;
     RECT  41.76 26.053 41.784 34.499 ;
     RECT  34.8 2.151 35.112 34.645 ;
     RECT  34.8 34.645 35.256 37.187 ;
     RECT  22.464 26.725 22.488 39.445 ;
     RECT  22.464 39.445 22.632 39.491 ;
     RECT  34.8 37.187 35.208 39.539 ;
     RECT  30.864 39.541 30.888 39.683 ;
     RECT  22.608 39.491 22.632 48.227 ;
     RECT  24 2.151 24.312 49.333 ;
     RECT  29.4 2.151 29.712 49.333 ;
     RECT  20.496 37.333 20.52 49.477 ;
     RECT  23.088 49.333 24.312 49.477 ;
     RECT  26.976 49.237 27 49.477 ;
     RECT  20.496 49.477 24.312 49.525 ;
     RECT  26.976 49.477 27.432 49.525 ;
     RECT  29.4 49.333 30.456 49.525 ;
     RECT  2.4 2.151 2.712 49.689 ;
     RECT  7.8 2.151 8.112 49.689 ;
     RECT  13.2 2.151 13.512 49.689 ;
     RECT  18.6 2.151 18.912 49.689 ;
     RECT  34.8 39.539 35.112 49.689 ;
     RECT  40.2 2.151 40.512 49.689 ;
     RECT  45.6 2.151 45.912 49.689 ;
     RECT  2.4 49.689 2.52 49.703 ;
     RECT  7.8 49.689 7.92 49.703 ;
     RECT  13.2 49.689 13.32 49.703 ;
     RECT  18.6 49.689 18.72 49.703 ;
     RECT  34.8 49.689 34.92 49.703 ;
     RECT  40.2 49.689 40.32 49.703 ;
     RECT  45.6 49.689 45.72 49.703 ;
     RECT  20.496 49.525 31.32 51.792 ;
     RECT  40.512 26.053 41.76 34.499 ;
     RECT  22.488 26.725 24 39.445 ;
     RECT  22.632 39.445 24 48.227 ;
     RECT  29.712 39.541 30.864 39.683 ;
     RECT  22.608 48.227 24 49.333 ;
     RECT  22.608 49.333 23.088 49.477 ;
  END
END dsfd_vm_static_read_v6
END LIBRARY
